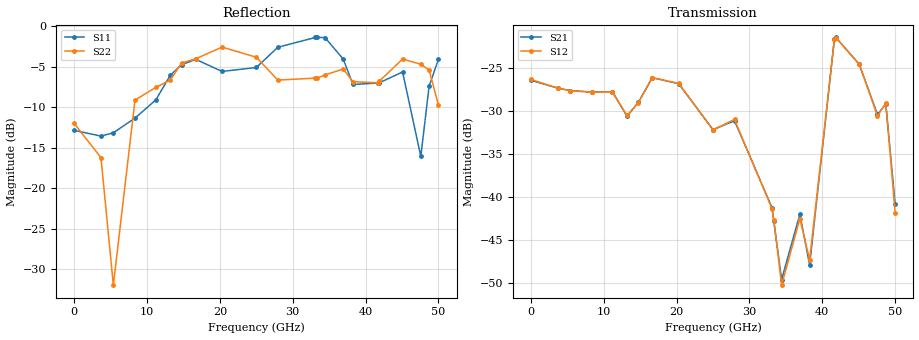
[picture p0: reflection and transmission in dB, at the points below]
!Keysight Technologies,N5245B,MY58422270,A.16.20.02
!Date: Thursday, March 05, 2026 01:34:56
!Correction: S11(C  2-Port  )
!S21(C  2-Port  )
!S12(C  2-Port  )
!S22(C  2-Port  )
!S2P File: Measurements: S11, S21, S12, S22:
# Hz S  dB  R 50
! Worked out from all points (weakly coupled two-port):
!   3201 points, 10 MHz to 50 GHz, reference 50 ohm
!   highest |S21| = -21.48 dB at 41.86 GHz (marker M1); lowest = -49.6 dB at 34.42 GHz (marker M2)
!   lowest |S11| = -16.1 dB at 47.58 GHz (marker M3), VSWR 1.37, Z = 45.4 + j14.4 ohm
!   |S11| at or under -10 dB: start of sweep to 9.802 GHz; 11.44 GHz to 11.87 GHz (423.4 MHz wide, 3.63 % of centre); 46.74 GHz to 48.32 GHz (1.577 GHz wide, 3.32 % of centre)
!   |S22| runs from -32.0 to -2.5 dB; largest |S21 - S12| = 0.0022
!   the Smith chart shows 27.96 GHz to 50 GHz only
!   S11 on the Smith chart (normalised r, x): 27.96 GHz: 0.20, +0.57; 33.11 GHz: 0.66, +2.65; 36.92 GHz: 1.53, -1.93; 47.58 GHz: 0.91, +0.29; 50 GHz: 0.54, -1.08
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1e7  -12.85 -3.5  -26.46 7.2  -26.35 5.5  -12.00 29.8
3.681141e9  -13.56 -96.8  -27.36 -136.5  -27.36 -136.5  -16.22 -158.8
5.383925e9  -13.15 -133.5  -27.65 156.9  -27.67 156.8  -31.98 -135.1
8.352081e9  -11.34 170.1  -27.82 32.5  -27.84 32.3  -9.11 -147.5
1.121088e10  -9.09 101.0  -27.79 -69.9  -27.82 -70.0  -7.54 93.6
1.321048e10  -6.02 61.3  -30.64 -119.8  -30.54 -119.9  -6.63 -16.7
1.474143e10  -4.75 13.9  -29.03 -148.0  -29.08 -148.2  -4.53 -87.7
1.667854e10  -4.07 -44.5  -26.15 157.6  -26.14 157.6  -4.01 -141.6
2.030282e10  -5.57 -126.3  -26.86 40.9  -26.82 40.9  -2.56 154.2
2.5005e10  -5.08 171.0  -32.18 -66.3  -32.22 -66.4  -3.81 70.7
2.795753e10  -2.58 119.4  -31.16 -131.8  -30.99 -131.9  -6.64 17.2
3.311275e10  -1.37 39.4  -41.24 16.0  -41.40 12.3  -6.39 -125.3
3.334708e10  -1.36 35.5  -42.79 5.7  -42.65 0.6  -6.40 -130.6
3.442499e10  -1.38 16.9  -49.57 -99.5  -50.22 -102.5  -6.00 -154.4
3.692449e10  -4.03 -37.2  -42.00 95.1  -42.51 100.0  -5.27 156.8
3.826797e10  -7.18 -20.5  -47.88 99.5  -47.27 99.4  -6.83 134.1
4.167354e10  -7.00 -56.6  -21.62 -61.5  -21.63 -61.1  -6.97 113.2
4.1861e10  -6.98 -56.6  -21.48 -79.4  -21.52 -79.6  -6.79 112.0
4.507911e10  -5.64 -105.5  -24.60 87.4  -24.60 87.2  -4.04 75.8
4.757861e10  -16.08 99.2  -30.42 -11.9  -30.62 -12.1  -4.68 42.0
4.871901e10  -7.38 -26.3  -29.22 -88.9  -29.08 -88.9  -5.40 19.5
5e10  -4.08 -77.8  -40.80 -135.8  -41.80 -131.7  -9.73 6.6
